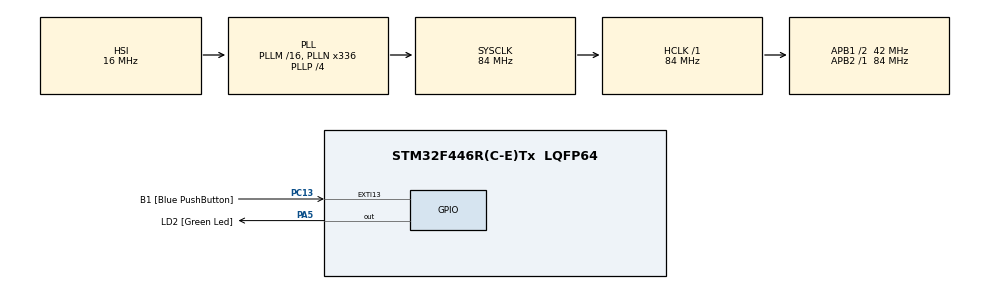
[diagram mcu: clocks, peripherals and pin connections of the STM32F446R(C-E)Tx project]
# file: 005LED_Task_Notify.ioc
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Mcu.Family=STM32F4
Mcu.Name=STM32F446R(C-E)Tx
Mcu.Package=LQFP64
NVIC.PriorityGroup=NVIC_PRIORITYGROUP_4
NVIC.TIM6_DAC_IRQn=true\:15\:0\:false\:false\:true\:false\:true
NVIC.TimeBase=TIM6_DAC_IRQn
NVIC.TimeBaseIP=TIM6
PA13.GPIO_Label=TMS
PA13.Signal=SYS_JTMS-SWDIO
PA14.GPIO_Label=TCK
PA14.Signal=SYS_JTCK-SWCLK
PA2.GPIO_Label=USART_TX
PA2.Signal=USART2_TX
PA3.GPIO_Label=USART_RX
PA3.Signal=USART2_RX
PA5.GPIO_Label=LD2 [Green Led]
PA5.Signal=GPIO_Output
PB3.GPIO_Label=SWO
PB3.Signal=SYS_JTDO-SWO
PC13.GPIO_Label=B1 [Blue PushButton]
PC13.GPIO_ModeDefaultEXTI=GPIO_MODE_IT_FALLING
PC13.Signal=GPXTI13
PC14-OSC32_IN.Signal=RCC_OSC32_IN
PC15-OSC32_OUT.Signal=RCC_OSC32_OUT
PH0-OSC_IN.Signal=RCC_OSC_IN
PH1-OSC_OUT.Signal=RCC_OSC_OUT
ProjectManager.HeapSize=0x200
ProjectManager.StackSize=0x400
ProjectManager.TargetToolchain=STM32CubeIDE
RCC.AHBFreq_Value=84000000
RCC.APB1CLKDivider=RCC_HCLK_DIV2
RCC.APB1Freq_Value=42000000
RCC.APB1TimFreq_Value=84000000
RCC.APB2Freq_Value=84000000
RCC.APB2TimFreq_Value=84000000
RCC.CortexFreq_Value=84000000
RCC.FLatency-AdvancedSettings=FLASH_LATENCY_2
RCC.HCLKFreq_Value=84000000
RCC.HSE_VALUE=8000000
RCC.HSI_VALUE=16000000
RCC.LSE_VALUE=32768
RCC.PLLN=336
RCC.PLLP=RCC_PLLP_DIV4
RCC.SYSCLKFreq_VALUE=84000000
RCC.SYSCLKSource=RCC_SYSCLKSOURCE_PLLCLK
RCC.USBFreq_Value=168000000
RCC.VCOOutputFreq_Value=336000000
VP_SYS_VS_tim6.Mode=TIM6
board=NUCLEO-F446RE

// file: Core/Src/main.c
#include "main.h"
#include "FreeRTOS.h"
#include "task.h"

#define DWT_CTRL    (*(volatile uint32_t*)0xE0001000)

void SystemClock_Config(void);
static void MX_GPIO_Init(void);
static void led1_handler(void* parameters);
static void led2_handler(void* parameters);
static void led3_handler(void* parameters);
static void button_handler(void* parameters);

TaskHandle_t led1_handle;
TaskHandle_t led2_handle;
TaskHandle_t led3_handle;
TaskHandle_t btn_handle;

TaskHandle_t volatile next_task_handle = NULL;

int main(void)
{
	BaseType_t status;

	HAL_Init();

	SystemClock_Config();

	MX_GPIO_Init();

	/* Enable the CYCCNT counter */
	DWT_CTRL |= ( 1 << 0);

	/* Task 1 creation (LED 1) */
	status = xTaskCreate(led1_handler, "LED1_task", 200, NULL, 3, &led1_handle);
	configASSERT(status == pdPASS);

	next_task_handle = led1_handle;

	/* Task 2 creation (LED 2) */
	status = xTaskCreate(led2_handler, "LED2_task", 200, NULL, 2, &led2_handle);
	configASSERT(status == pdPASS);

	/* Task 3 creation (LED 3) */
	status = xTaskCreate(led3_handler, "LED3_task", 200, NULL, 1, &led3_handle);
	configASSERT(status == pdPASS);

	/* Task 4 creation (Button) */
	status = xTaskCreate(button_handler, "Button_task", 200, NULL, 4, &btn_handle);
	configASSERT(status == pdPASS);

	/* Start the scheduler */
	vTaskStartScheduler();

	while (1)
	{

	}

}

void SystemClock_Config(void)
{
  RCC_OscInitTypeDef RCC_OscInitStruct = {0};
  RCC_ClkInitTypeDef RCC_ClkInitStruct = {0};

  /** Configure the main internal regulator output voltage
  */
  __HAL_RCC_PWR_CLK_ENABLE();
  __HAL_PWR_VOLTAGESCALING_CONFIG(PWR_REGULATOR_VOLTAGE_SCALE3);
  /** Initializes the RCC Oscillators according to the specified parameters
  * in the RCC_OscInitTypeDef structure.
  */
  RCC_OscInitStruct.OscillatorType = RCC_OSCILLATORTYPE_HSI;
  RCC_OscInitStruct.HSIState = RCC_HSI_ON;
  RCC_OscInitStruct.HSICalibrationValue = RCC_HSICALIBRATION_DEFAULT;
  RCC_OscInitStruct.PLL.PLLState = RCC_PLL_ON;
  RCC_OscInitStruct.PLL.PLLSource = RCC_PLLSOURCE_HSI;
  RCC_OscInitStruct.PLL.PLLM = 16;
  RCC_OscInitStruct.PLL.PLLN = 336;
  RCC_OscInitStruct.PLL.PLLP = RCC_PLLP_DIV4;
  RCC_OscInitStruct.PLL.PLLQ = 2;
  RCC_OscInitStruct.PLL.PLLR = 2;
  if (HAL_RCC_OscConfig(&RCC_OscInitStruct) != HAL_OK)
  {
    Error_Handler();
  }
  /** Initializes the CPU, AHB and APB buses clocks
  */
  RCC_ClkInitStruct.ClockType = RCC_CLOCKTYPE_HCLK|RCC_CLOCKTYPE_SYSCLK
                              |RCC_CLOCKTYPE_PCLK1|RCC_CLOCKTYPE_PCLK2;
  RCC_ClkInitStruct.SYSCLKSource = RCC_SYSCLKSOURCE_PLLCLK;
  RCC_ClkInitStruct.AHBCLKDivider = RCC_SYSCLK_DIV1;
  RCC_ClkInitStruct.APB1CLKDivider = RCC_HCLK_DIV2;
  RCC_ClkInitStruct.APB2CLKDivider = RCC_HCLK_DIV1;

  if (HAL_RCC_ClockConfig(&RCC_ClkInitStruct, FLASH_LATENCY_2) != HAL_OK)
  {
    Error_Handler();
  }
}

static void MX_GPIO_Init(void)
{
  GPIO_InitTypeDef GPIO_InitStruct = {0};

  /* GPIO Ports Clock Enable */
  __HAL_RCC_GPIOC_CLK_ENABLE();
  __HAL_RCC_GPIOH_CLK_ENABLE();
  __HAL_RCC_GPIOA_CLK_ENABLE();
  __HAL_RCC_GPIOB_CLK_ENABLE();

  /*Configure GPIO pin Output Level */
  HAL_GPIO_WritePin(LD2_GPIO_Port, LD2_Pin, GPIO_PIN_RESET);

  /*Configure GPIO pin : B1_Pin */
  GPIO_InitStruct.Pin = B1_Pin;
  GPIO_InitStruct.Mode = GPIO_MODE_IT_FALLING;
  GPIO_InitStruct.Pull = GPIO_NOPULL;
  HAL_GPIO_Init(B1_GPIO_Port, &GPIO_InitStruct);

  /*Configure GPIO pins : USART_TX_Pin USART_RX_Pin */
  GPIO_InitStruct.Pin = USART_TX_Pin|USART_RX_Pin;
  GPIO_InitStruct.Mode = GPIO_MODE_AF_PP;
  GPIO_InitStruct.Pull = GPIO_NOPULL;
  GPIO_InitStruct.Speed = GPIO_SPEED_FREQ_VERY_HIGH;
  GPIO_InitStruct.Alternate = GPIO_AF7_USART2;
  HAL_GPIO_Init(GPIOA, &GPIO_InitStruct);

  /*Configure GPIO pin : LD2_Pin */
  GPIO_InitStruct.Pin = LD2_Pin;
  GPIO_InitStruct.Mode = GPIO_MODE_OUTPUT_PP;
  GPIO_InitStruct.Pull = GPIO_NOPULL;
  GPIO_InitStruct.Speed = GPIO_SPEED_FREQ_LOW;
  HAL_GPIO_Init(LD2_GPIO_Port, &GPIO_InitStruct);

  /* Configure LED tasks GPIO pins */
  GPIO_InitStruct.Pin = GPIO_PIN_0;
  GPIO_InitStruct.Mode = GPIO_MODE_OUTPUT_PP;
  GPIO_InitStruct.Pull = GPIO_NOPULL;
  GPIO_InitStruct.Speed = GPIO_SPEED_FREQ_LOW;
  HAL_GPIO_Init(GPIOA, &GPIO_InitStruct);

  GPIO_InitStruct.Pin = GPIO_PIN_1;
  HAL_GPIO_Init(GPIOA, &GPIO_InitStruct);

  GPIO_InitStruct.Pin = GPIO_PIN_4;
  HAL_GPIO_Init(GPIOA, &GPIO_InitStruct);
}

static void led1_handler(void *parameters)
{
	BaseType_t status;

	while(1)
	{
		HAL_GPIO_TogglePin(GPIOA, GPIO_PIN_0);
		status = xTaskNotifyWait(0, 0, NULL, pdMS_TO_TICKS(1000));
		if (status == pdTRUE)
		{
			vTaskSuspendAll();
			next_task_handle = led2_handle;
			xTaskResumeAll();
			HAL_GPIO_WritePin(GPIOA, GPIO_PIN_0, GPIO_PIN_SET);
			vTaskDelete(NULL);
		}
	}
}

static void led2_handler(void *parameters)
{
	BaseType_t status;

	while(1)
	{
		HAL_GPIO_TogglePin(GPIOA, GPIO_PIN_1);
		status = xTaskNotifyWait(0, 0, NULL, pdMS_TO_TICKS(800));
		if (status == pdTRUE)
		{
			vTaskSuspendAll();
			next_task_handle = led3_handle;
			xTaskResumeAll();
			HAL_GPIO_WritePin(GPIOA, GPIO_PIN_1, GPIO_PIN_SET);
			vTaskDelete(NULL);
		}
	}
}

static void led3_handler(void *parameters)
{
	BaseType_t status;

	while(1)
	{
		HAL_GPIO_TogglePin(GPIOA, GPIO_PIN_4);
		status = xTaskNotifyWait(0, 0, NULL, pdMS_TO_TICKS(400));
		if (status == pdTRUE)
		{
			vTaskSuspendAll();
			next_task_handle = NULL;
			xTaskResumeAll();
			HAL_GPIO_WritePin(GPIOA, GPIO_PIN_4, GPIO_PIN_SET);
			vTaskDelete(btn_handle);
			vTaskDelete(NULL);
		}
	}
}

static void button_handler(void *parameters)
{
	uint8_t button_read = 1;
	uint8_t prev_read = 1;

	while(1)
	{
		button_read = HAL_GPIO_ReadPin(B1_GPIO_Port, B1_Pin);
		if (!button_read)
		{
			if (prev_read)
				xTaskNotify(next_task_handle, 0, eNoAction);
		}
		prev_read = button_read;
		vTaskDelay(pdMS_TO_TICKS(10));
	}
}

void HAL_TIM_PeriodElapsedCallback(TIM_HandleTypeDef *htim)
{
  if (htim->Instance == TIM6) {
    HAL_IncTick();
  }
}

void Error_Handler(void)
{
  __disable_irq();
  while (1)
  {
  }
}
